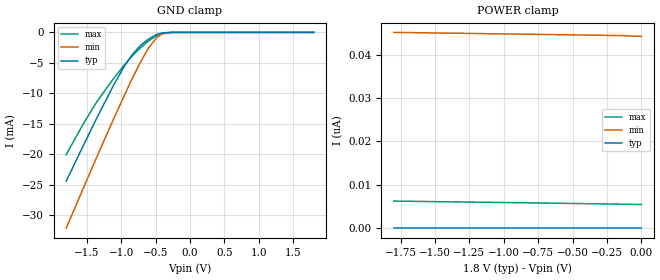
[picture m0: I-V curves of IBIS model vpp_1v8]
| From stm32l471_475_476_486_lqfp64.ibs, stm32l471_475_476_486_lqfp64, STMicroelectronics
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|   Model vpp_1v8
[Model]  vpp_1v8
Model_type Input
Polarity   Non-Inverting
Vinl =   0.540000V
Vinh =   1.260000V
C_comp   2.988700pF   2.961600pF   3.012500pF
[Temperature Range]   25.000000   0.140000k   -40.000000
[Pullup Reference]   1.800000V   1.600000V   2.000000V
[Pulldown Reference]   0.0V   0.0V   0.0V
[POWER Clamp Reference]   1.800000V   1.600000V   2.000000V
[GND Clamp Reference]   0.0V   0.0V   0.0V
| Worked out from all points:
|   GND clamp passes 1 mA (typ) near -0.59 V on its own axis
[GND_clamp]
|Voltage   I(typ)   I(min)   I(max)
-1.8V     -24.41mA   -32.12mA   -20.05mA
-1.56V    -18.78mA   -25.79mA   -15.18mA
-1.36V    -14.17mA   -20.57mA   -11.46mA
-1.12V    -8.861mA   -14.43mA   -7.7mA
-960mV    -5.648mA   -10.45mA   -5.416mA
-840mV    -3.649mA   -7.579mA   -3.849mA
-720mV    -2.141mA   -4.873mA   -2.536mA
-600mV    -1.071mA   -2.496mA   -1.387mA
-480mV    -333.4uA   -797.3uA   -478.8uA
-400mV    -83.74uA   -240.3uA   -125.2uA
-280mV    -3.85uA    -21.22uA   -3.758uA
1.8V      0A         44.22nA    5.344nA
[POWER_clamp]
|Voltage   I(typ)   I(min)   I(max)
-1.8V     0A         45.18nA    6.242nA
-1.12V    0A         44.88nA    5.961nA
-720mV    0A         44.7nA     5.791nA
-380mV    0A         44.54nA    5.64nA
-140mV    0A         44.43nA    5.526nA
-120mV    0A         44.41nA    5.515nA
-60mV     0A         44.32nA    5.485nA
-40mV     0A         44.29nA    5.475nA
0V        0A         44.25nA    5.454nA
